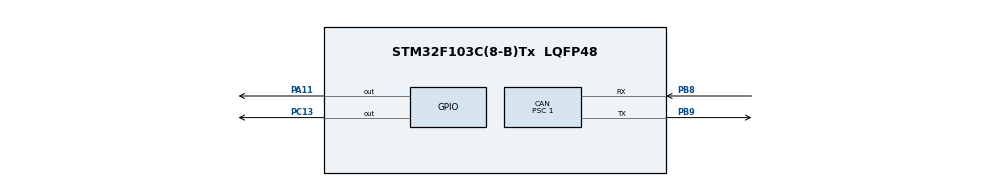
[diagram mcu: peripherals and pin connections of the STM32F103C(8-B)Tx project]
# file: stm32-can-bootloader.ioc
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CAN.BS1=CAN_BS1_9TQ
CAN.BS2=CAN_BS2_6TQ
CAN.CalculateTimeBit=4000
CAN.CalculateTimeQuantum=250.0
CAN.NART=ENABLE
CAN.Prescaler=1
Mcu.Family=STM32F1
Mcu.Name=STM32F103C(8-B)Tx
Mcu.Package=LQFP48
NVIC.PriorityGroup=NVIC_PRIORITYGROUP_4
NVIC.USB_LP_CAN1_RX0_IRQn=true\:5\:0\:true\:false\:true\:true\:true
PA11.Signal=GPIO_Output
PA13.Mode=Serial_Wire
PA13.Signal=SYS_JTMS-SWDIO
PA14.Mode=Serial_Wire
PA14.Signal=SYS_JTCK-SWCLK
PB8.Mode=Master
PB8.Signal=CAN_RX
PB9.Mode=Master
PB9.Signal=CAN_TX
PC13-TAMPER-RTC.Signal=GPIO_Output
PD0-OSC_IN.Mode=HSE-External-Clock-Source
PD0-OSC_IN.Signal=RCC_OSC_IN
PD1-OSC_OUT.Mode=HSE-External-Clock-Source
PD1-OSC_OUT.Signal=RCC_OSC_OUT
ProjectManager.HeapSize=0x200
ProjectManager.StackSize=0x400
ProjectManager.TargetToolchain=MDK-ARM V5
RCC.AHBFreq_Value=8000000
RCC.APB1CLKDivider=RCC_HCLK_DIV2
RCC.APB1Freq_Value=4000000
RCC.APB1TimFreq_Value=8000000
RCC.APB2Freq_Value=8000000
RCC.APB2TimFreq_Value=8000000
RCC.HCLKFreq_Value=8000000
RCC.PLLMUL=RCC_PLL_MUL6
RCC.PLLSourceVirtual=RCC_PLLSOURCE_HSE
RCC.SYSCLKFreq_VALUE=8000000
RCC.USBFreq_Value=48000000
VP_CRC_VS_CRC.Mode=CRC_Activate
board=CANBOOT

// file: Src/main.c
/**
  ******************************************************************************
  * File Name          : main.c
  * Description        : Main program body
  ******************************************************************************
  *
  * COPYRIGHT(c) 2019 STMicroelectronics
  *
  * Redistribution and use in source and binary forms, with or without modification,
  * are permitted provided that the following conditions are met:
  *   1. Redistributions of source code must retain the above copyright notice,
  *      this list of conditions and the following disclaimer.
  *   2. Redistributions in binary form must reproduce the above copyright notice,
  *      this list of conditions and the following disclaimer in the documentation
  *      and/or other materials provided with the distribution.
  *   3. Neither the name of STMicroelectronics nor the names of its contributors
  *      may be used to endorse or promote products derived from this software
  *      without specific prior written permission.
  *
  * THIS SOFTWARE IS PROVIDED BY THE COPYRIGHT HOLDERS AND CONTRIBUTORS "AS IS"
  * AND ANY EXPRESS OR IMPLIED WARRANTIES, INCLUDING, BUT NOT LIMITED TO, THE
  * IMPLIED WARRANTIES OF MERCHANTABILITY AND FITNESS FOR A PARTICULAR PURPOSE ARE
  * DISCLAIMED. IN NO EVENT SHALL THE COPYRIGHT HOLDER OR CONTRIBUTORS BE LIABLE
  * FOR ANY DIRECT, INDIRECT, INCIDENTAL, SPECIAL, EXEMPLARY, OR CONSEQUENTIAL
  * DAMAGES (INCLUDING, BUT NOT LIMITED TO, PROCUREMENT OF SUBSTITUTE GOODS OR
  * SERVICES; LOSS OF USE, DATA, OR PROFITS; OR BUSINESS INTERRUPTION) HOWEVER
  * CAUSED AND ON ANY THEORY OF LIABILITY, WHETHER IN CONTRACT, STRICT LIABILITY,
  * OR TORT (INCLUDING NEGLIGENCE OR OTHERWISE) ARISING IN ANY WAY OUT OF THE USE
  * OF THIS SOFTWARE, EVEN IF ADVISED OF THE POSSIBILITY OF SUCH DAMAGE.
  *
  ******************************************************************************
  */
#include "main.h"
#include "stm32f1xx_hal.h"

/* USER CODE BEGIN Includes */
#include <string.h>

#define  WAIT_HOST    0
#define IDLE        1
#define PAGE_PROG    2

typedef void (*pFunction)(void);

// Flash configuration
#define MAIN_PROGRAM_START_ADDRESS              (uint32_t)0x08002000
#define BOOTLOADER_PROGRAM_START_ADDRESS        (uint32_t)0x08000000
#define MAIN_PROGRAM_PAGE_NUMBER                8
#define NUM_OF_PAGES                            (64)

// CAN identifiers
#define DEVICE_CAN_ID                            0x78E
#define CMD_HOST_INIT                            0x01
#define CMD_PAGE_PROG                            0x02
#define CMD_BOOT                                0x03

#define CAN_RESP_OK                              0x01
#define CAN_RESP_ERROR                          0x02
/* USER CODE END Includes */

CAN_HandleTypeDef hcan;

CRC_HandleTypeDef hcrc;

HAL_StatusTypeDef canTxStatus;
HAL_StatusTypeDef canRxStatus;
/* USER CODE BEGIN PV */
/* Private variables ---------------------------------------------------------*/
static CanTxMsgTypeDef        canTxMessage;
static CanRxMsgTypeDef        canRxMessage;
static FLASH_EraseInitTypeDef eraseInitStruct;

pFunction                     JumpAddress;
uint8_t                       PageBuffer[FLASH_PAGE_SIZE];
volatile int                  PageBufferPtr;
uint8_t                       PageIndex;
int                           PageCRC;

volatile uint8_t              blState;

/* USER CODE END PV */

void SystemClock_Config(void);
void Error_Handler(void);
static void MX_GPIO_Init(void);
static void MX_CAN_Init(void);
static void MX_CRC_Init(void);

/* USER CODE BEGIN PFP */
/* Private function prototypes -----------------------------------------------*/

/* USER CODE END PFP */

/* USER CODE BEGIN 0 */
void JumpToApplication()
{
  JumpAddress = *(__IO pFunction*)(MAIN_PROGRAM_START_ADDRESS + 4);
  __set_MSP(*(__IO uint32_t*) MAIN_PROGRAM_START_ADDRESS);
  HAL_DeInit();
  JumpAddress();
}

HAL_StatusTypeDef TransmitResponsePacket(uint8_t response)
{
  hcan.pTxMsg->StdId = DEVICE_CAN_ID;
  hcan.pTxMsg->DLC = 1;
  hcan.pTxMsg->Data[0] = response;
  return HAL_CAN_Transmit(&hcan,1);
}

void HAL_CAN_RxCpltCallback(CAN_HandleTypeDef* CanHandle)
{
  // Skip messages not intended for our device
  if (CanHandle->pRxMsg->StdId != DEVICE_CAN_ID && CanHandle->pRxMsg->ExtId != DEVICE_CAN_ID) {
    HAL_CAN_Receive_IT(&hcan, CAN_FIFO0);
    return;
  }

  if (blState == PAGE_PROG)
  {
    memcpy(&PageBuffer[PageBufferPtr],
      CanHandle->pRxMsg->Data,
      CanHandle->pRxMsg->DLC);
    PageBufferPtr += CanHandle->pRxMsg->DLC;

    if (PageBufferPtr == FLASH_PAGE_SIZE) {
      HAL_NVIC_DisableIRQ(USB_LP_CAN1_RX0_IRQn);

      HAL_GPIO_TogglePin(GPIOA, GPIO_PIN_11);
      uint32_t crc = HAL_CRC_Calculate(&hcrc, (uint32_t*)PageBuffer, FLASH_PAGE_SIZE / 4);

      //if (crc == PageCRC && PageIndex <= NUM_OF_PAGES)
			if (PageIndex <= NUM_OF_PAGES)
      {
        HAL_FLASH_Unlock();

        uint32_t PageError = 0;

        eraseInitStruct.TypeErase = TYPEERASE_PAGES;
        eraseInitStruct.PageAddress = BOOTLOADER_PROGRAM_START_ADDRESS + PageIndex * FLASH_PAGE_SIZE;
        eraseInitStruct.NbPages = 1;

        HAL_FLASHEx_Erase(&eraseInitStruct, &PageError);

        for (int i = 0; i < FLASH_PAGE_SIZE; i += 4)
        {
          HAL_FLASH_Program(TYPEPROGRAM_WORD, BOOTLOADER_PROGRAM_START_ADDRESS + PageIndex * FLASH_PAGE_SIZE + i, *(uint32_t*)&PageBuffer[i]);
        }

        HAL_FLASH_Lock();

        TransmitResponsePacket(CAN_RESP_OK);
      }
      else
      {
        TransmitResponsePacket(CAN_RESP_ERROR);
      }

      blState = IDLE;

      HAL_NVIC_EnableIRQ(USB_LP_CAN1_RX0_IRQn);
    }

    HAL_GPIO_TogglePin(GPIOC, GPIO_PIN_13);
    HAL_CAN_Receive_IT(&hcan, CAN_FIFO0);
    return;
  }

  switch(CanHandle->pRxMsg->Data[0])
  {
    case CMD_HOST_INIT:
      blState = IDLE;
      TransmitResponsePacket(CAN_RESP_OK);
      break;
    case CMD_PAGE_PROG:
      if (blState == IDLE) {
				// очищает страницу
        memset(PageBuffer, 0, FLASH_PAGE_SIZE);
				//контрольная сумма
        memcpy(&PageCRC, &CanHandle->pRxMsg->Data[2], sizeof(int));
				// номер страницы
        PageIndex = CanHandle->pRxMsg->Data[1] + MAIN_PROGRAM_PAGE_NUMBER;
        blState = PAGE_PROG;
        PageBufferPtr = 0;
      } else {
        // Should never get here
      }
      break;
    case CMD_BOOT:
      TransmitResponsePacket(CAN_RESP_OK);
      JumpToApplication();
      break;
    default:
      break;
  }

  HAL_GPIO_TogglePin(GPIOC, GPIO_PIN_13);
  HAL_CAN_Receive_IT(&hcan, CAN_FIFO0);
}
/* USER CODE END 0 */

int main(void)
{

  /* MCU Configuration----------------------------------------------------------*/

  /* Reset of all peripherals, Initializes the Flash interface and the Systick. */
  HAL_Init();

  /* Configure the system clock */
  SystemClock_Config();

  /* Initialize all configured peripherals */
  MX_GPIO_Init();
  MX_CAN_Init();
  MX_CRC_Init();

  /* USER CODE BEGIN 2 */
  hcan.pTxMsg = &canTxMessage;
  hcan.pRxMsg = &canRxMessage;

  CAN_FilterConfTypeDef canFilterConfig;
  canFilterConfig.FilterNumber = 0;
  canFilterConfig.FilterMode = CAN_FILTERMODE_IDMASK;
  canFilterConfig.FilterScale = CAN_FILTERSCALE_32BIT;
  canFilterConfig.FilterIdHigh = 0x0000;
  canFilterConfig.FilterIdLow = 0x0000;
  canFilterConfig.FilterMaskIdHigh = 0x0000 << 5;
  canFilterConfig.FilterMaskIdLow = 0x0000;
  canFilterConfig.FilterFIFOAssignment = 0;
  canFilterConfig.FilterActivation = ENABLE;
  canFilterConfig.BankNumber = 1;
  HAL_CAN_ConfigFilter(&hcan, &canFilterConfig);

  HAL_GPIO_WritePin(GPIOA, GPIO_PIN_11, GPIO_PIN_SET);
	//PC13 почему то инверсный
	HAL_GPIO_WritePin(GPIOC, GPIO_PIN_13, GPIO_PIN_RESET);

  HAL_CAN_Receive_IT(&hcan, CAN_FIFO0);
  HAL_Delay(5000);

  HAL_GPIO_WritePin(GPIOA, GPIO_PIN_11, GPIO_PIN_RESET);
  HAL_GPIO_WritePin(GPIOC, GPIO_PIN_13, GPIO_PIN_SET);

  // Timed out waiting for host
  if (blState == WAIT_HOST) {
    JumpToApplication();
  }
  /* USER CODE END 2 */

  /* Infinite loop */
  while (1)
  {
//  canTxStatus = TransmitResponsePacket(CAN_RESP_OK);
//	HAL_Delay(100);
  }

}

/** System Clock Configuration
*/
void SystemClock_Config(void)
{

  RCC_OscInitTypeDef RCC_OscInitStruct;
  RCC_ClkInitTypeDef RCC_ClkInitStruct;
  RCC_PeriphCLKInitTypeDef PeriphClkInit;

    /**Initializes the CPU, AHB and APB busses clocks
    */
  RCC_OscInitStruct.OscillatorType = RCC_OSCILLATORTYPE_LSI|RCC_OSCILLATORTYPE_HSE;
  RCC_OscInitStruct.HSEState = RCC_HSE_ON;
  RCC_OscInitStruct.HSEPredivValue = RCC_HSE_PREDIV_DIV1;
  RCC_OscInitStruct.HSIState = RCC_HSI_ON;
  RCC_OscInitStruct.LSIState = RCC_LSI_ON;
  RCC_OscInitStruct.PLL.PLLState = RCC_PLL_ON;
  RCC_OscInitStruct.PLL.PLLSource = RCC_PLLSOURCE_HSE;
  RCC_OscInitStruct.PLL.PLLMUL = RCC_PLL_MUL9;
  if (HAL_RCC_OscConfig(&RCC_OscInitStruct) != HAL_OK)
  {
    Error_Handler();
  }

    /**Initializes the CPU, AHB and APB busses clocks
    */
  RCC_ClkInitStruct.ClockType = RCC_CLOCKTYPE_HCLK|RCC_CLOCKTYPE_SYSCLK
                              |RCC_CLOCKTYPE_PCLK1|RCC_CLOCKTYPE_PCLK2;
  RCC_ClkInitStruct.SYSCLKSource = RCC_SYSCLKSOURCE_PLLCLK;
  RCC_ClkInitStruct.AHBCLKDivider = RCC_SYSCLK_DIV1;
  RCC_ClkInitStruct.APB1CLKDivider = RCC_HCLK_DIV2;
  RCC_ClkInitStruct.APB2CLKDivider = RCC_HCLK_DIV1;

  if (HAL_RCC_ClockConfig(&RCC_ClkInitStruct, FLASH_LATENCY_2) != HAL_OK)
  {
    Error_Handler();
  }

  PeriphClkInit.PeriphClockSelection = RCC_PERIPHCLK_RTC;
  PeriphClkInit.RTCClockSelection = RCC_RTCCLKSOURCE_LSI;
  if (HAL_RCCEx_PeriphCLKConfig(&PeriphClkInit) != HAL_OK)
  {
    Error_Handler();
  }

    /**Configure the Systick interrupt time
    */
  HAL_SYSTICK_Config(HAL_RCC_GetHCLKFreq()/1000);

    /**Configure the Systick
    */
  HAL_SYSTICK_CLKSourceConfig(SYSTICK_CLKSOURCE_HCLK);

  /* SysTick_IRQn interrupt configuration */
  HAL_NVIC_SetPriority(SysTick_IRQn, 0, 0);
}

/* CAN init function */
static void MX_CAN_Init(void)
{

  hcan.Instance = CAN1;
  hcan.Init.Prescaler = 1;
  hcan.Init.Mode = CAN_MODE_NORMAL;
  hcan.Init.SJW = CAN_SJW_1TQ;
  hcan.Init.BS1 = CAN_BS1_9TQ;
  hcan.Init.BS2 = CAN_BS2_6TQ;
  hcan.Init.TTCM = DISABLE;
  hcan.Init.ABOM = DISABLE;
  hcan.Init.AWUM = DISABLE;
  hcan.Init.NART = ENABLE;
  hcan.Init.RFLM = DISABLE;
  hcan.Init.TXFP = DISABLE;
  if (HAL_CAN_Init(&hcan) != HAL_OK)
  {
    Error_Handler();
  }

}

/* CRC init function */
static void MX_CRC_Init(void)
{

  hcrc.Instance = CRC;
  if (HAL_CRC_Init(&hcrc) != HAL_OK)
  {
    Error_Handler();
  }

}

/** Configure pins as
        * Analog
        * Input
        * Output
        * EVENT_OUT
        * EXTI
*/
static void MX_GPIO_Init(void)
{

  GPIO_InitTypeDef GPIO_InitStruct;

  /* GPIO Ports Clock Enable */
  __HAL_RCC_GPIOD_CLK_ENABLE();
  __HAL_RCC_GPIOA_CLK_ENABLE();
	__HAL_RCC_GPIOB_CLK_ENABLE();
  __HAL_RCC_GPIOC_CLK_ENABLE();

  /*Configure GPIO pin Output Level */
  HAL_GPIO_WritePin(GPIOA, GPIO_PIN_11, GPIO_PIN_RESET);

  /*Configure GPIO pins : PA11 */
  GPIO_InitStruct.Pin = GPIO_PIN_11;
  GPIO_InitStruct.Mode = GPIO_MODE_OUTPUT_PP;
  GPIO_InitStruct.Speed = GPIO_SPEED_FREQ_LOW;
  HAL_GPIO_Init(GPIOA, &GPIO_InitStruct);

	  /*Configure GPIO pin Output Level */
	HAL_GPIO_WritePin(GPIOC, GPIO_PIN_13, GPIO_PIN_RESET);

  /*Configure GPIO pins : PC13 */
  GPIO_InitStruct.Pin = GPIO_PIN_13;
  GPIO_InitStruct.Mode = GPIO_MODE_OUTPUT_PP;
  GPIO_InitStruct.Speed = GPIO_SPEED_FREQ_LOW;
  HAL_GPIO_Init(GPIOC, &GPIO_InitStruct);

}

void Error_Handler(void)
{
  while(1)
  {
  }
}

/************************ (C) COPYRIGHT STMicroelectronics *****END OF FILE****/
